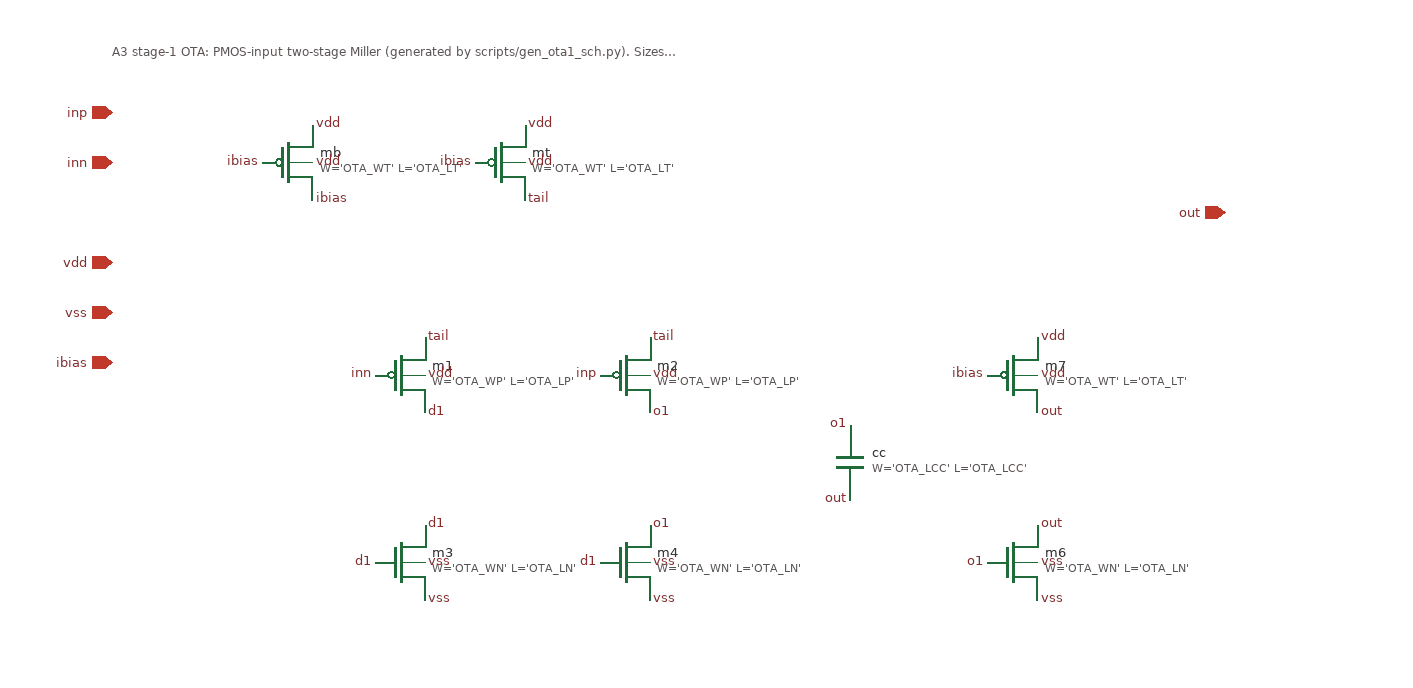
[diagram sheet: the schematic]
v {xschem version=3.4.7 file_version=1.2}
G {}
K {}
V {}
S {}
E {}
C {symbols/pfet_03v3.sym} -420 -260 0 0 {name=mb
L='OTA_LT'
W='OTA_WT'
nf=1
m='OTA_KB'
ad='DIFF*OTA_WT*0.18u'
as='DIFF*OTA_WT*0.18u'
pd='DIFF*2*(OTA_WT+0.18u)'
ps='DIFF*2*(OTA_WT+0.18u)'
nrd=0
nrs=0
sa=0 sb=0 sd=0
model=pfet_03v3
spiceprefix=X}
C {lab_pin.sym} -400 -290 0 1 {name=p1 sig_type=std_logic lab=vdd}
C {lab_pin.sym} -400 -230 0 1 {name=p2 sig_type=std_logic lab=ibias}
C {lab_pin.sym} -440 -260 0 0 {name=p3 sig_type=std_logic lab=ibias}
C {lab_pin.sym} -400 -260 0 1 {name=p4 sig_type=std_logic lab=vdd}
C {symbols/pfet_03v3.sym} -250 -260 0 0 {name=mt
L='OTA_LT'
W='OTA_WT'
nf=1
m='OTA_KT'
ad='DIFF*OTA_WT*0.18u'
as='DIFF*OTA_WT*0.18u'
pd='DIFF*2*(OTA_WT+0.18u)'
ps='DIFF*2*(OTA_WT+0.18u)'
nrd=0
nrs=0
sa=0 sb=0 sd=0
model=pfet_03v3
spiceprefix=X}
C {lab_pin.sym} -230 -290 0 1 {name=p5 sig_type=std_logic lab=vdd}
C {lab_pin.sym} -230 -230 0 1 {name=p6 sig_type=std_logic lab=tail}
C {lab_pin.sym} -270 -260 0 0 {name=p7 sig_type=std_logic lab=ibias}
C {lab_pin.sym} -230 -260 0 1 {name=p8 sig_type=std_logic lab=vdd}
C {symbols/pfet_03v3.sym} -330 -90 0 0 {name=m1
L='OTA_LP'
W='OTA_WP'
nf=1
m='OTA_KP'
ad='DIFF*OTA_WP*0.18u'
as='DIFF*OTA_WP*0.18u'
pd='DIFF*2*(OTA_WP+0.18u)'
ps='DIFF*2*(OTA_WP+0.18u)'
nrd=0
nrs=0
sa=0 sb=0 sd=0
model=pfet_03v3
spiceprefix=X}
C {lab_pin.sym} -310 -120 0 1 {name=p9 sig_type=std_logic lab=tail}
C {lab_pin.sym} -310 -60 0 1 {name=p10 sig_type=std_logic lab=d1}
C {lab_pin.sym} -350 -90 0 0 {name=p11 sig_type=std_logic lab=inn}
C {lab_pin.sym} -310 -90 0 1 {name=p12 sig_type=std_logic lab=vdd}
C {symbols/pfet_03v3.sym} -150 -90 0 0 {name=m2
L='OTA_LP'
W='OTA_WP'
nf=1
m='OTA_KP'
ad='DIFF*OTA_WP*0.18u'
as='DIFF*OTA_WP*0.18u'
pd='DIFF*2*(OTA_WP+0.18u)'
ps='DIFF*2*(OTA_WP+0.18u)'
nrd=0
nrs=0
sa=0 sb=0 sd=0
model=pfet_03v3
spiceprefix=X}
C {lab_pin.sym} -130 -120 0 1 {name=p13 sig_type=std_logic lab=tail}
C {lab_pin.sym} -130 -60 0 1 {name=p14 sig_type=std_logic lab=o1}
C {lab_pin.sym} -170 -90 0 0 {name=p15 sig_type=std_logic lab=inp}
C {lab_pin.sym} -130 -90 0 1 {name=p16 sig_type=std_logic lab=vdd}
C {symbols/nfet_03v3.sym} -330 60 0 0 {name=m3
L='OTA_LN'
W='OTA_WN'
nf=1
m='OTA_KN'
ad='DIFF*OTA_WN*0.18u'
as='DIFF*OTA_WN*0.18u'
pd='DIFF*2*(OTA_WN+0.18u)'
ps='DIFF*2*(OTA_WN+0.18u)'
nrd=0
nrs=0
sa=0 sb=0 sd=0
model=nfet_03v3
spiceprefix=X}
C {lab_pin.sym} -310 30 0 1 {name=p17 sig_type=std_logic lab=d1}
C {lab_pin.sym} -310 90 0 1 {name=p18 sig_type=std_logic lab=vss}
C {lab_pin.sym} -350 60 0 0 {name=p19 sig_type=std_logic lab=d1}
C {lab_pin.sym} -310 60 0 1 {name=p20 sig_type=std_logic lab=vss}
C {symbols/nfet_03v3.sym} -150 60 0 0 {name=m4
L='OTA_LN'
W='OTA_WN'
nf=1
m='OTA_KN'
ad='DIFF*OTA_WN*0.18u'
as='DIFF*OTA_WN*0.18u'
pd='DIFF*2*(OTA_WN+0.18u)'
ps='DIFF*2*(OTA_WN+0.18u)'
nrd=0
nrs=0
sa=0 sb=0 sd=0
model=nfet_03v3
spiceprefix=X}
C {lab_pin.sym} -130 30 0 1 {name=p21 sig_type=std_logic lab=o1}
C {lab_pin.sym} -130 90 0 1 {name=p22 sig_type=std_logic lab=vss}
C {lab_pin.sym} -170 60 0 0 {name=p23 sig_type=std_logic lab=d1}
C {lab_pin.sym} -130 60 0 1 {name=p24 sig_type=std_logic lab=vss}
C {symbols/pfet_03v3.sym} 160 -90 0 0 {name=m7
L='OTA_LT'
W='OTA_WT'
nf=1
m='OTA_K7'
ad='DIFF*OTA_WT*0.18u'
as='DIFF*OTA_WT*0.18u'
pd='DIFF*2*(OTA_WT+0.18u)'
ps='DIFF*2*(OTA_WT+0.18u)'
nrd=0
nrs=0
sa=0 sb=0 sd=0
model=pfet_03v3
spiceprefix=X}
C {lab_pin.sym} 180 -120 0 1 {name=p25 sig_type=std_logic lab=vdd}
C {lab_pin.sym} 180 -60 0 1 {name=p26 sig_type=std_logic lab=out}
C {lab_pin.sym} 140 -90 0 0 {name=p27 sig_type=std_logic lab=ibias}
C {lab_pin.sym} 180 -90 0 1 {name=p28 sig_type=std_logic lab=vdd}
C {symbols/nfet_03v3.sym} 160 60 0 0 {name=m6
L='OTA_LN'
W='OTA_WN'
nf=1
m='OTA_K6'
ad='DIFF*OTA_WN*0.18u'
as='DIFF*OTA_WN*0.18u'
pd='DIFF*2*(OTA_WN+0.18u)'
ps='DIFF*2*(OTA_WN+0.18u)'
nrd=0
nrs=0
sa=0 sb=0 sd=0
model=nfet_03v3
spiceprefix=X}
C {lab_pin.sym} 180 30 0 1 {name=p29 sig_type=std_logic lab=out}
C {lab_pin.sym} 180 90 0 1 {name=p30 sig_type=std_logic lab=vss}
C {lab_pin.sym} 140 60 0 0 {name=p31 sig_type=std_logic lab=o1}
C {lab_pin.sym} 180 60 0 1 {name=p32 sig_type=std_logic lab=vss}
C {symbols/cap_mim_2f0fF.sym} 30 -20 0 0 {name=cc
W='OTA_LCC'
L='OTA_LCC'
model=cap_mim_2f0_m2m3_noshield
spiceprefix=X
m=1}
C {lab_pin.sym} 30 -50 3 0 {name=p33 sig_type=std_logic lab=o1}
C {lab_pin.sym} 30 10 1 0 {name=p34 sig_type=std_logic lab=out}
C {ipin.sym} -560 -300 0 0 {name=io35 lab=inp}
C {ipin.sym} -560 -260 0 0 {name=io36 lab=inn}
C {opin.sym} 330 -220 0 1 {name=io37 lab=out}
C {iopin.sym} -560 -180 0 0 {name=io38 lab=vdd}
C {iopin.sym} -560 -140 0 0 {name=io39 lab=vss}
C {ipin.sym} -560 -100 0 0 {name=io40 lab=ibias}
T {A3 stage-1 OTA: PMOS-input two-stage Miller (generated by scripts/gen_ota1_sch.py). Sizes = spice/ota1_params.spice.} -560 -360 0 0 0.3 0.3 {}
